VERSION 5.7 ;
NAMESCASESENSITIVE ON ;
BUSBITCHARS "[]" ;
DIVIDERCHAR "/" ;

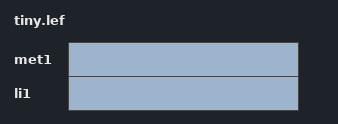
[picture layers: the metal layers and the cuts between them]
LAYER li1
  TYPE ROUTING ;
END li1

LAYER met1
  TYPE ROUTING ;
END met1

MACRO sky130_fd_sc_hd__inv_1
  PIN A
    DIRECTION INPUT ;
  END A
  PIN Y
    DIRECTION OUTPUT ;
  END Y
END sky130_fd_sc_hd__inv_1

END LIBRARY
